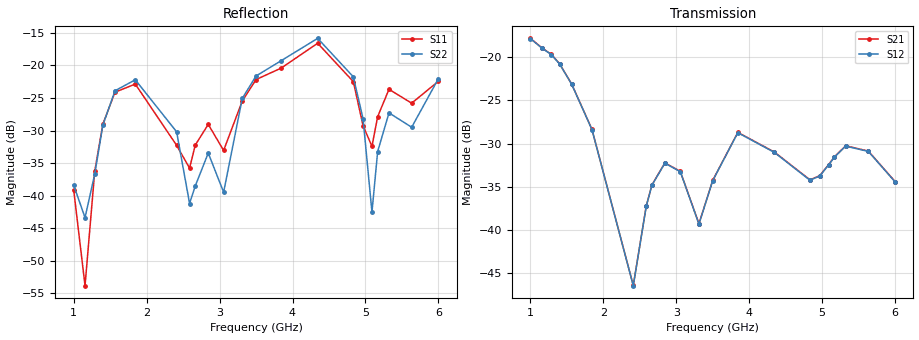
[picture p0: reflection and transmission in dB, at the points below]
!Agilent Technologies,E8364B,MY43040528,A.07.50.67
!Agilent E8364B: A.07.50.67
!Date: Sunday, March 01, 2026 15:38:19
!Correction: S11(Full 2 Port(1,2))
!S21(Full 2 Port(1,2))
!S12(Full 2 Port(1,2))
!S22(Full 2 Port(1,2))
!S2P File: Measurements: S11, S21, S12, S22:
# Hz S  dB  R 50
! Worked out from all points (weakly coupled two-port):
!   451 points, 1 GHz to 6 GHz, reference 50 ohm
!   highest |S21| = -17.86 dB at 1 GHz (marker M1); lowest = -46.4 dB at 2.411 GHz (marker M2)
!   lowest |S11| = -53.8 dB at 1.156 GHz (marker M3), VSWR 1.00, Z = 49.9 + j0.17 ohm
!   |S11| at or under -10 dB: start of sweep to end of sweep
!   |S22| runs from -43.4 to -15.8 dB; largest |S21 - S12| = 0.00056
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1e9  -39.10 33.7  -17.86 27.6  -17.89 27.6  -38.40 -9.0
1.155556e9  -53.84 122.8  -18.93 -18.8  -18.96 -18.8  -43.38 48.5
1.288889e9  -36.22 -163.6  -19.72 -61.7  -19.75 -61.6  -36.67 109.3
1.4e9  -29.01 178.8  -20.78 -99.2  -20.81 -99.1  -29.16 98.9
1.566667e9  -24.10 142.0  -23.13 -154.3  -23.16 -154.3  -23.88 58.3
1.844444e9  -22.85 88.2  -28.36 119.6  -28.39 119.7  -22.20 -7.7
2.411111e9  -32.27 21.9  -46.38 -131.8  -46.41 -131.8  -30.19 -115.0
2.588889e9  -35.77 76.1  -37.20 97.7  -37.25 97.7  -41.21 -98.5
2.666667e9  -32.23 82.4  -34.78 62.7  -34.81 62.8  -38.51 -60.0
2.844444e9  -29.05 60.9  -32.23 -10.1  -32.27 -10.1  -33.46 -81.8
3.055556e9  -33.05 55.5  -33.21 -89.4  -33.25 -89.4  -39.47 -63.3
3.311111e9  -25.45 83.8  -39.25 -137.5  -39.30 -137.4  -25.06 -66.5
3.5e9  -22.16 56.4  -34.25 -154.0  -34.29 -153.9  -21.61 -108.2
3.844444e9  -20.40 26.9  -28.71 85.8  -28.75 85.9  -19.26 -160.0
4.344444e9  -16.58 -40.1  -30.98 -94.8  -31.02 -94.7  -15.83 108.6
4.833333e9  -22.48 -119.8  -34.19 53.9  -34.24 53.9  -21.74 1.7
4.966667e9  -29.23 -127.4  -33.71 -21.2  -33.75 -21.1  -28.17 -26.8
5.088889e9  -32.43 -67.3  -32.43 -87.8  -32.47 -87.8  -42.54 22.6
5.166667e9  -27.87 -54.6  -31.55 -127.3  -31.59 -127.3  -33.24 69.8
5.322222e9  -23.66 -72.7  -30.26 159.5  -30.30 159.5  -27.28 42.9
5.633333e9  -25.79 -99.2  -30.87 29.9  -30.91 29.9  -29.49 22.6
6e9  -22.42 -91.1  -34.39 -74.9  -34.43 -74.9  -22.01 -4.7
